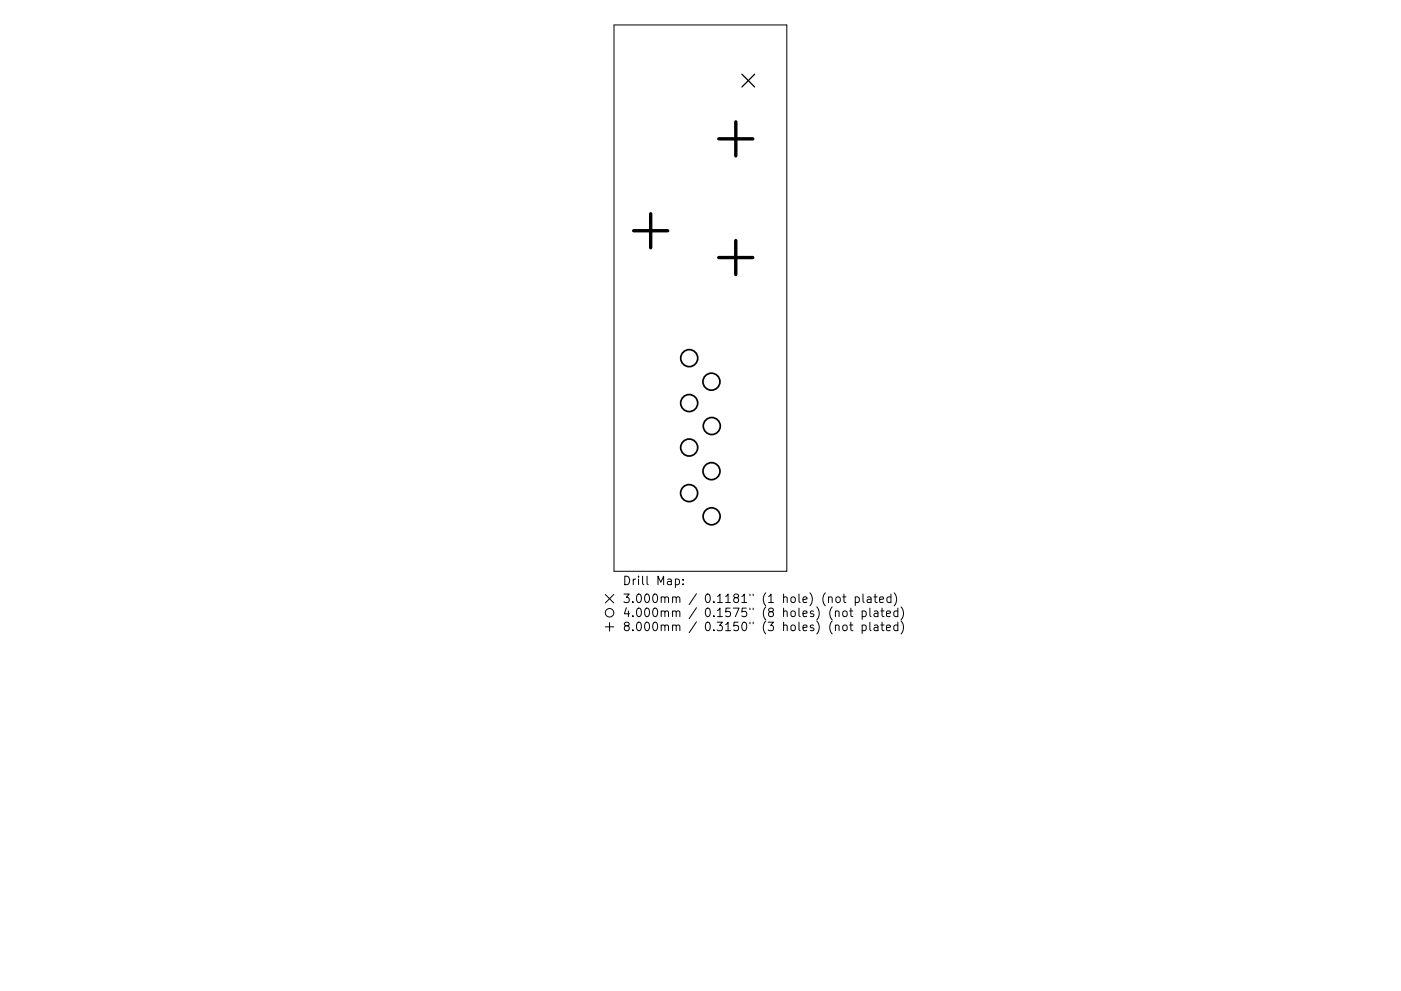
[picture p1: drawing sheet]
<svg xmlns="http://www.w3.org/2000/svg" width="297mm" height="210mm" viewBox="0 0 297 210" stroke-linecap="round" stroke-linejoin="round" font-family="sans-serif">
<defs><g id="words">
<g font-size="2.5">
<text x="131.9" y="124.1">Drill Map:</text>
<text x="131.9" y="127.9">3.000mm / 0.1181&quot; (1 hole) (not plated)</text>
<text x="131.9" y="130.9">4.000mm / 0.1575&quot; (8 holes) (not plated)</text>
<text x="131.9" y="133.9">8.000mm / 0.3150&quot; (3 holes) (not plated)</text>
</g>
</g></defs>
<g fill="none" stroke="#000" stroke-width=".21">
<path d="M130.2 5.3h36.6v115.9h-36.6zM128.3 126.1l1.8 1.8M128.3 133h1.8M129.2 132.1v1.8M130.1 126.1l-1.8 1.8M143.2 122.9h.5l.4 .3v.5l-.2 .3h-.7M144.8 123.9v.2M144.8 122.9v.2M175.7 126.8l.2-.2 .5 .1v1.1M177.1 129.8l.3-.2 .4 .1 .1 1.1M177.1 132.8l.3-.2 .4 .1 .1 1.1M177.4 126.7l.4-.1 .4 .4v.5l-.4 .3h-.4l-.2-.3v-.5z"/>
<path d="M178.7 126.6h.7M178.8 129.8l.2-.2 .5 .2 .1 .7-.2 .2-.4 .1-.2-.1zM178.8 132.7l.5-.1 .3 .4v.5l-.3 .3-.5-.1-.1-.2v-.5zM178.9 126v1.6l.5 .2M180.1 129.6h.7M180.1 132.6h.7M180.4 129v1.6l.4 .2M180.4 132v1.6l.4 .2M181.3 126.7l.6-.1 .3 .4v.5l-.2 .3h-.7M181.3 126.6v1.8M182.8 129.7l.5-.1 .4 .4v.5l-.2 .2h-.7M182.8 132.7l.5-.1 .4 .4v.5l-.2 .2h-.7"/>
<path d="M182.8 129.6v1.8M182.8 132.6v1.8M183 126v1.6l.2 .2M183.9 126.7h.7l.1 1.1M184.4 129v1.6l.3 .2M184.4 132v1.6l.3 .2M184.7 127.1l-.6 .1a.35 .35 0 0 0-.3 .3 .35 .35 0 0 0 .3 .3h.6M185.3 126.6h.7M185.4 129.7h.7v1.1M185.4 132.7h.7v1.1M185.5 126v1.6l.5 .2M186.1 130.1h-.6a.35 .35 0 0 0-.2 .4 .35 .35 0 0 0 .2 .3l.6-.1"/>
<path d="M186.1 133l-.6 .1a.35 .35 0 0 0-.2 .4 .35 .35 0 0 0 .2 .3l.6-.1M186.5 127.2l.8-.1v-.4l-.6-.1-.2 .3 .1 .9h.7M186.7 129.6h.7M186.7 132.6h.7M187 129v1.6l.4 .2M187 132v1.6l.4 .2M188 130.2l.8-.1-.1-.4-.5-.1-.2 .3v.8h.7M188 133.2l.8-.2-.1-.3-.5-.1-.2 .3v.8h.7M188.9 126.7l-.5-.1-.4 .4v.5l.2 .3h.7M188.9 126v1.8M189.6 125.8a2.07 2.07 0 0 1 0 2.7M190.4 129.7l-.6-.1-.3 .4v.5l.2 .2h.7"/>
<path d="M190.4 132.7l-.6-.1-.3 .4v.5l.2 .2h.7M190.4 129v1.8M190.4 132v1.8M191 128.8a2.07 2.07 0 0 1 0 2.7M191 131.7a2.07 2.07 0 0 1 0 2.8"/>
<circle cx="129.2" cy="130" r=".9"/>
</g>
<path d="M157.3 15.7l2.7 2.8M160 15.7l-2.7 2.8" fill="none" stroke="#000" stroke-width=".27"/>
<g fill="none" stroke="#000" stroke-width=".36">
<circle cx="146.1" cy="76" r="1.8"/>
<circle cx="146.1" cy="95" r="1.8"/>
<circle cx="146.1" cy="85.5" r="1.8"/>
<circle cx="150.8" cy="81" r="1.8"/>
<circle cx="150.8" cy="100" r="1.8"/>
<circle cx="150.9" cy="90.4" r="1.8"/>
<circle cx="146.1" cy="104.6" r="1.8"/>
<circle cx="150.9" cy="109.5" r="1.8"/>
</g>
<path d="M152.4 29.5h7.2M156 25.8v7.3M134.3 49h7.3M138 45.3v7.3M152.4 54.6h7.2M156 51v7.3" fill="none" stroke="#000" stroke-width=".72"/>
<use href="#words"/>
</svg>
